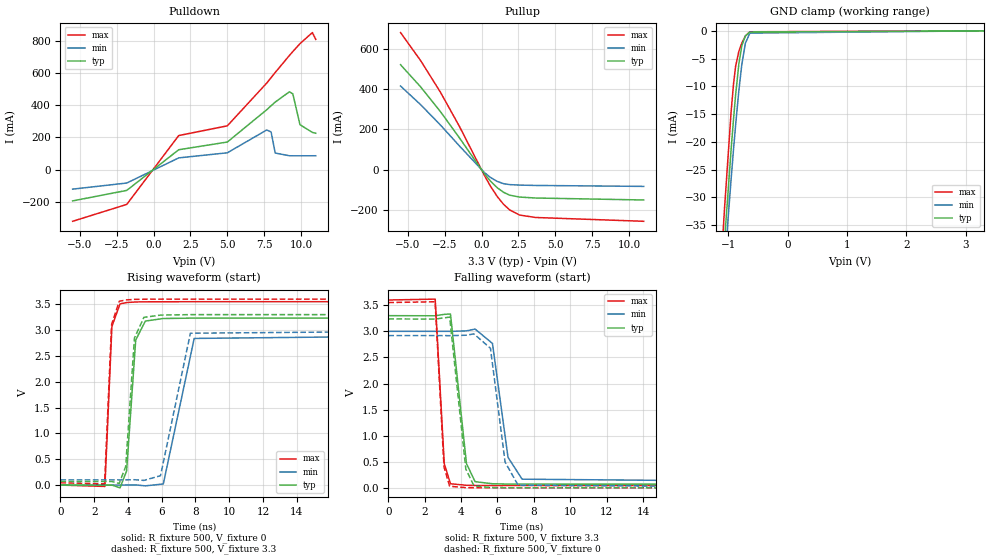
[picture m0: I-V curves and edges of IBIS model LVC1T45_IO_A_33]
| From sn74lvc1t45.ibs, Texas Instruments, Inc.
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[Model]   LVC1T45_IO_A_33
Model_type  I/O
Vinl=0.8
Vinh=2.0
Enable   Active-Low
Vref =   0
Rref =   2000
Cref =   15p
Vmeas =   1.65
| variable   typ   min   max
C_comp   6.86pF   5.92pF   8.09pF
| C_pullup   10.82pF   9.16pF   12.69pF
| C_pulldown   10.11pF   7.31pF   13.23pF
| C_tri-state   6.86pF   5.92pF   8.09pF
[Temperature Range]   40   100   -40
| Ambient temperature   25   85   -40
[Voltage range]   3.3   3   3.6
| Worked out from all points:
|   slope of the pulldown table from 0 to 0.495 V, typ, clamps not added: 11.2 ohm
|   slope of the pullup table from 0 to 0.495 V, typ, clamps not added: 10.6 ohm
|   GND clamp passes 1 mA (typ) near -0.71 V on its own axis
|   rising waveform, R_fixture 500, V_fixture 0: 20-80 % time 360ps typ, 624ps min, 211ps max; typ from 0 V to 3.23 V
|   falling waveform, R_fixture 500, V_fixture 3.3: 20-80 % time 352ps typ, 619ps min, 218ps max; typ from 3.3 V to 0.069 V
|   rising waveform, R_fixture 500, V_fixture 3.3: 20-80 % time 358ps typ, 630ps min, 216ps max; typ from 0.069 V to 3.3 V
|   falling waveform, R_fixture 500, V_fixture 0: 20-80 % time 344ps typ, 584ps min, 213ps max; typ from 3.24 V to 0 V
[GND Clamp]
| LVC1T45_IO_A_33
|   Voltage   I(typ)   I(min)   I(max)
-5.5V     -910.9mA   -836.3mA   -1.031A
-1.12V    -47.12mA   -50.9mA    -42.25mA
-1.09V    -42.34mA   -46.45mA   -36.95mA
-1.06V    -37.63mA   -42.05mA   -31.78mA
-950mV    -21.32mA   -26.62mA   -14.52mA
-910mV    -15.92mA   -21.37mA   -9.573mA
-875mV    -11.59mA   -17mA      -6.417mA
-820mV    -5.939mA   -10.75mA   -3.68mA
-770mV    -2.643mA   -6.035mA   -2.191mA
-710mV    -920.7uA   -2.212mA   -923.3uA
-635mV    -221.2uA   -410.8uA   -171uA
3.3V      10.41pA    35.81nA    8.12pA
[Pulldown]
| LVC1T45_IO_A_33
|   Voltage   I(typ)   I(min)   I(max)
-5.5V     -194.6mA   -121.5mA   -321.3mA
-1.825V   -129.3mA   -83.52mA   -216.3mA
1.7V      123.2mA    72.65mA    211.3mA
5V        171.2mA    104.3mA    271.8mA
7.675V    372mA      246.2mA    537.6mA
7.97V     396.6mA    233.5mA    571.4mA
8.25V     419.5mA    102.9mA    603.3mA
9.215V    483.4mA    85.88mA    709.4mA
9.445V    469.9mA    85.7mA     733.5mA
9.93V     278.8mA    85.68mA    782.4mA
10.77V    230.9mA    85.86mA    851.2mA
11V       225.9mA    85.92mA    808.7mA
[Pullup]
| LVC1T45_IO_A_33
|   Voltage   I(typ)   I(min)   I(max)
-5.5V     521mA      415.5mA    680.3mA
-4.125V   410.3mA    322.3mA    540.3mA
-2.79V    288.4mA    222mA      384.5mA
-1.5V     158.2mA    118.3mA    215mA
195mV     -19.51mA   -13.56mA   -27.85mA
640mV     -58.63mA   -39.42mA   -85.46mA
1.07V     -88.98mA   -57.5mA    -132.8mA
1.49V     -111.1mA   -68.41mA   -170.4mA
1.9V      -125.3mA   -73.08mA   -198.2mA
2.575V    -134.8mA   -75.52mA   -223.8mA
3.665V    -139.5mA   -77.22mA   -236mA
11V       -149.3mA   -81.96mA   -254.9mA
[Ramp]
| LVC1T45_IO_A_33
| variable   typ   min   max
dV/dt_r   1.98/3.73E-10   1.79/6.46E-10   2.16/2.23E-10
dV/dt_f   1.97/3.66E-10   1.77/6.35E-10   2.17/2.33E-10
R_load = 500
[Rising Waveform]
| LVC1T45_IO_A_33
R_fixture =   500
C_fixture =   0
L_fixture =   0
V_fixture =   0
V_fixture_min = 0
V_fixture_max = 0
|   Time   V(typ)   V(min)   V(max)
0s        168.9pV    331.3pV    105.2pV
2.635ns   535.9uV    -2.708uV   -26.37mV
3.05ns    328.1uV    25.37uV    3.071V
3.53ns    -54.05mV   -143.3uV   3.507V
3.92ns    272.3mV    949.2uV    3.534V
4.46ns    2.808V     3.006mV    3.545V
5.03ns    3.175V     -15.41mV   3.548V
6.095ns   3.225V     21.1mV     3.549V
7.925ns   3.233V     2.839V     3.55V
29.99ns   3.234V     2.914V     3.55V
[Falling Waveform]
| LVC1T45_IO_A_33
R_fixture =   500
C_fixture =   0
L_fixture =   0
V_fixture =   3.3
V_fixture_min = 3
V_fixture_max = 3.6
|   Time   V(typ)   V(min)   V(max)
0s        3.3V       3V         3.6V
2.575ns   3.298V     3V         3.617V
3.075ns   3.325V     3V         462.9mV
3.415ns   3.333V     2.999V     78.23mV
4.295ns   465.1mV    3.009V     49.31mV
4.77ns    118.4mV    3.043V     46.61mV
5.725ns   78.71mV    2.768V     44.83mV
6.58ns    72.54mV    585.1mV    44.39mV
7.355ns   70.73mV    166.2mV    44.25mV
29.99ns   69.38mV    100.9mV    44.1mV
[Rising Waveform]
| LVC1T45_IO_A_33
R_fixture =   500
C_fixture =   0
L_fixture =   0
V_fixture =   3.3
V_fixture_min = 3
V_fixture_max = 3.6
|   Time   V(typ)   V(min)   V(max)
0s        69.31mV    100.8mV    44.06mV
2.615ns   69.7mV     100.8mV    24.07mV
3.03ns    70.18mV    100.8mV    3.107V
3.48ns    30.68mV    100.6mV    3.557V
3.865ns   357.1mV    101.4mV    3.584V
4.385ns   2.846V     103.5mV    3.595V
4.945ns   3.247V     90.25mV    3.598V
5.93ns    3.291V     181.5mV    3.6V
7.7ns     3.3V       2.94V      3.6V
29.99ns   3.3V       3V         3.6V
[Falling Waveform]
| LVC1T45_IO_A_33
R_fixture =   500
C_fixture =   0
L_fixture =   0
V_fixture =   0
V_fixture_min = 0
V_fixture_max = 0
|   Time   V(typ)   V(min)   V(max)
0s        3.237V     2.918V     3.551V
2.57ns    3.235V     2.918V     3.567V
3.06ns    3.258V     2.918V     399.8mV
3.37ns    3.272V     2.917V     31mV
4.26ns    360.9mV    2.925V     4.439mV
4.705ns   39.48mV    2.951V     2.252mV
5.615ns   7.22mV     2.675V     712.3uV
6.42ns    2.499mV    493.6mV    318.2uV
7.135ns   1.128mV    52.09mV    185.7uV
29.99ns   70.43uV    137.7uV    35.57uV
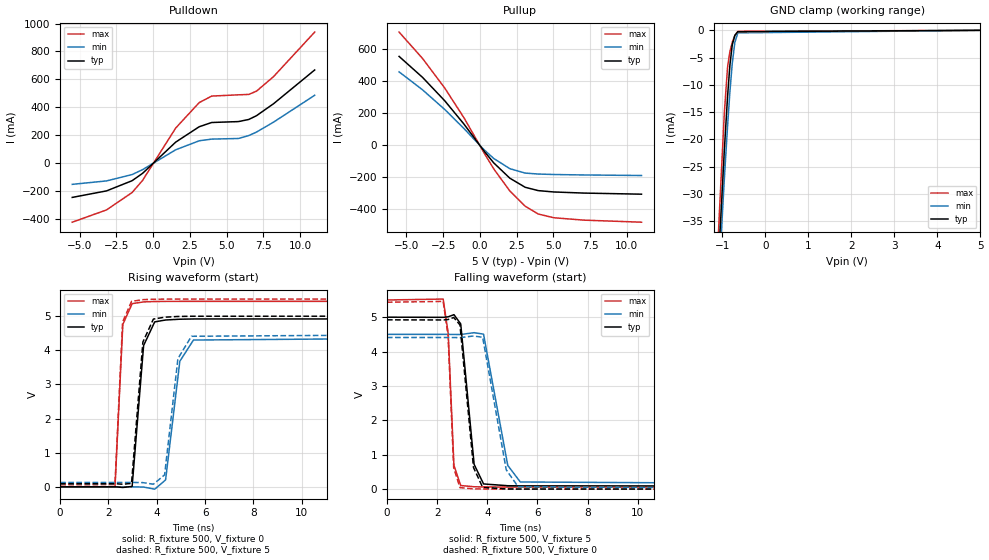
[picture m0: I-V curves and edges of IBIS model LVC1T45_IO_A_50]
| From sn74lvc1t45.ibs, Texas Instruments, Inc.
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[Model]   LVC1T45_IO_A_50
Model_type  I/O
Vinl=1.35
Vinh=3.85
Enable   Active-Low
Vref =   0
Rref =   2000
Cref =   15p
Vmeas =   2.5
| variable   typ   min   max
C_comp   6.40pF   5.43pF   7.87pF
| C_pullup   10.12pF   8.52pF   12.70pF
| C_pulldown   8.71pF   6.85pF   10.92pF
| C_tri-state   6.40pF   5.43pF   7.87pF
[Temperature Range]   40   100   -40
| Ambient temperature   25   85   -40
[Voltage range]   5   4.5   5.5
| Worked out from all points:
|   slope of the pulldown table from 0 to 0.75 V, typ, clamps not added: 9.75 ohm
|   slope of the pullup table from 0 to 0.75 V, typ, clamps not added: 8.46 ohm
|   GND clamp passes 1 mA (typ) near -0.71 V on its own axis
|   rising waveform, R_fixture 500, V_fixture 0: 20-80 % time 252ps typ, 390ps min, 153ps max; typ from 0 V to 4.92 V
|   falling waveform, R_fixture 500, V_fixture 5: 20-80 % time 277ps typ, 406ps min, 178ps max; typ from 5 V to 0.092 V
|   rising waveform, R_fixture 500, V_fixture 5: 20-80 % time 244ps typ, 377ps min, 152ps max; typ from 0.092 V to 5 V
|   falling waveform, R_fixture 500, V_fixture 0: 20-80 % time 275ps typ, 397ps min, 172ps max; typ from 4.92 V to 0 V
[GND Clamp]
| LVC1T45_IO_A_50
|   Voltage   I(typ)   I(min)   I(max)
-5.5V     -910.9mA   -836.3mA   -1.031A
-1.135V   -49.53mA   -53.14mA   -44.94mA
-1.12V    -47.12mA   -50.9mA    -42.25mA
-1.1V     -43.92mA   -47.92mA   -38.71mA
-1.07V    -39.19mA   -43.51mA   -33.49mA
-955mV    -22.02mA   -27.29mA   -15.21mA
-880mV    -12.18mA   -17.61mA   -6.789mA
-825mV    -6.376mA   -11.28mA   -3.86mA
-770mV    -2.643mA   -6.035mA   -2.191mA
-710mV    -920.7uA   -2.212mA   -923.3uA
-640mV    -245.9uA   -461.9uA   -195.8uA
5V        15.38pA    101.8nA    12.33pA
[Pulldown]
| LVC1T45_IO_A_50
|   Voltage   I(typ)   I(min)   I(max)
-5.5V     -247.8mA   -154.1mA   -425.7mA
-3.17V    -201.1mA   -129.5mA   -337.6mA
-1.43V    -128.1mA   -83.89mA   -213mA
-715mV    -75.2mA    -48.65mA   -125.8mA
1.54V     149mA      93.97mA    250mA
3.14V     259.4mA    158.6mA    432.6mA
3.99V     289.7mA    170.6mA    479.4mA
5.81V     296.3mA    175mA      488.4mA
6.515V    311.6mA    196.1mA    491.3mA
7.04V     338.7mA    221.1mA    514.8mA
8.205V    424.9mA    292.7mA    619.5mA
11V       666.8mA    485.2mA    938.6mA
[Pullup]
| LVC1T45_IO_A_50
|   Voltage   I(typ)   I(min)   I(max)
-5.5V     556.3mA    459.8mA    708.3mA
-3.9V     425mA      347.2mA    543mA
-2.385V   278.3mA    224.1mA    357.5mA
-1.08V    132.9mA    105.2mA    172.2mA
260mV     -32.41mA   -24.88mA   -42.78mA
945mV     -109.3mA   -81.77mA   -146.9mA
2.04V     -204.9mA   -145.3mA   -285mA
3.085V    -261.6mA   -172.9mA   -380mA
3.975V    -282.4mA   -178.8mA   -428.7mA
5.03V     -290.8mA   -181.7mA   -451.9mA
7.055V    -297.7mA   -184.5mA   -466.8mA
11V       -304.7mA   -188mA     -479.7mA
[Ramp]
| LVC1T45_IO_A_50
| variable   typ   min   max
dV/dt_r   2.99/2.63E-10   2.69/4.00E-10   3.30/1.61E-10
dV/dt_f   2.99/2.91E-10   2.66/4.21E-10   3.32/1.85E-10
R_load = 500
[Rising Waveform]
| LVC1T45_IO_A_50
R_fixture =   500
C_fixture =   0
L_fixture =   0
V_fixture =   0
V_fixture_min = 0
V_fixture_max = 0
|   Time   V(typ)   V(min)   V(max)
0s        225.7pV    389.5pV    145.6pV
2.27ns    2.056mV    38.75uV    -7.16mV
2.595ns   -17.16mV   -92.81uV   4.758V
2.98ns    12.86mV    1.984mV    5.366V
3.455ns   4.14V      -5.989mV   5.417V
3.915ns   4.832V     -67.18mV   5.428V
4.365ns   4.887V     203.4mV    5.431V
4.955ns   4.91V      3.679V     5.433V
5.52ns    4.917V     4.3V       5.433V
24.99ns   4.92V      4.406V     5.433V
[Falling Waveform]
| LVC1T45_IO_A_50
R_fixture =   500
C_fixture =   0
L_fixture =   0
V_fixture =   5
V_fixture_min = 4.5
V_fixture_max = 5.5
|   Time   V(typ)   V(min)   V(max)
0s        5V         4.5V       5.5V
2.24ns    4.996V     4.5V       5.527V
2.44ns    5.011V     4.5V       4.536V
2.67ns    5.073V     4.498V     691.2mV
2.94ns    4.805V     4.496V     105.1mV
3.475ns   720.4mV    4.55V      70.03mV
3.85ns    152.1mV    4.506V     64.85mV
4.815ns   99.98mV    691.1mV    61.17mV
5.315ns   95.69mV    208.9mV    60.67mV
24.99ns   91.93mV    128.8mV    60.15mV
[Rising Waveform]
| LVC1T45_IO_A_50
R_fixture =   500
C_fixture =   0
L_fixture =   0
V_fixture =   5
V_fixture_min = 4.5
V_fixture_max = 5.5
|   Time   V(typ)   V(min)   V(max)
0s        91.89mV    128.7mV    60.13mV
2.27ns    93.94mV    128.7mV    67.41mV
2.585ns   76.47mV    128.6mV    4.824V
2.955ns   101.7mV    130.4mV    5.432V
3.425ns   4.24V      124.6mV    5.483V
3.86ns    4.914V     77.89mV    5.494V
4.325ns   4.969V     351.4mV    5.498V
4.875ns   4.99V      3.756V     5.499V
5.435ns   4.997V     4.41V      5.5V
24.99ns   5V         4.5V       5.5V
[Falling Waveform]
| LVC1T45_IO_A_50
R_fixture =   500
C_fixture =   0
L_fixture =   0
V_fixture =   0
V_fixture_min = 0
V_fixture_max = 0
|   Time   V(typ)   V(min)   V(max)
0s        4.923V     4.41V      5.435V
2.24ns    4.919V     4.41V      5.459V
2.435ns   4.932V     4.41V      4.475V
2.66ns    4.991V     4.408V     624.1mV
2.91ns    4.776V     4.405V     44.54mV
3.45ns    629.4mV    4.453V     9.068mV
3.815ns   52.93mV    4.416V     4.396mV
4.755ns   6.967mV    563.1mV    994.9uV
5.23ns    3.351mV    67.88mV    527.3uV
24.99ns   37.65uV    72.57uV    18.81uV
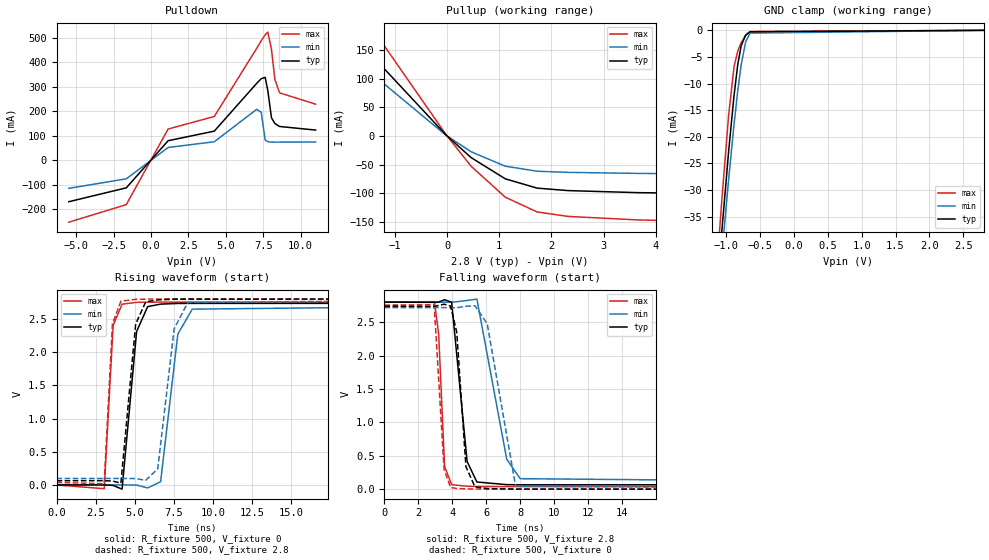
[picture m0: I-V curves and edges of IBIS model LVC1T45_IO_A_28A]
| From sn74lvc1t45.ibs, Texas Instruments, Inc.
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[Model]   LVC1T45_IO_A_28A
Model_type  I/O
Vinl=0.7
Vinh=1.7
Enable   Active-Low
Vref =   0
Rref =   2000
Cref =   15p
Vmeas =   1.25
| variable   typ   min   max
C_comp   7.02pF   6.20pF   8.13pF
| C_pullup   10.99pF   9.76pF   12.54pF
| C_pulldown   10.57pF   7.61pF   14.13pF
| C_tri-state   7.02pF   6.20pF   8.13pF
[Temperature Range]   40   100   -40
| Ambient temperature   25   85   -40
[Voltage range]   2.8   2.8   2.8
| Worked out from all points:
|   slope of the pulldown table from 0 to 0.42 V, typ, clamps not added: 12.3 ohm
|   slope of the pullup table from 0 to 0.42 V, typ, clamps not added: 12.2 ohm
|   GND clamp passes 1 mA (typ) near -0.71 V on its own axis
|   rising waveform, R_fixture 500, V_fixture 0: 20-80 % time 434ps typ, 689ps min, 276ps max; typ from 0 V to 2.74 V
|   falling waveform, R_fixture 500, V_fixture 2.8: 20-80 % time 417ps typ, 691ps min, 266ps max; typ from 2.8 V to 0.064 V
|   rising waveform, R_fixture 500, V_fixture 2.8: 20-80 % time 436ps typ, 703ps min, 278ps max; typ from 0.064 V to 2.8 V
|   falling waveform, R_fixture 500, V_fixture 0: 20-80 % time 402ps typ, 646ps min, 260ps max; typ from 2.74 V to 0 V
[GND Clamp]
| LVC1T45_IO_A_28A
|   Voltage   I(typ)   I(min)   I(max)
-5.5V     -910.9mA   -836.3mA   -1.031A
-1.14V    -50.34mA   -53.89mA   -45.85mA
-1.12V    -47.12mA   -50.9mA    -42.25mA
-1.075V   -39.97mA   -44.24mA   -34.35mA
-1.06V    -37.63mA   -42.05mA   -31.78mA
-960mV    -22.72mA   -27.97mA   -15.92mA
-880mV    -12.18mA   -17.61mA   -6.789mA
-825mV    -6.376mA   -11.28mA   -3.86mA
-775mV    -2.883mA   -6.453mA   -2.321mA
-710mV    -920.7uA   -2.212mA   -923.3uA
-645mV    -272.8uA   -519.5uA   -223.5uA
2.8V      8.953pA    15.32pA    7.945pA
[Pulldown]
| LVC1T45_IO_A_28A
|   Voltage   I(typ)   I(min)   I(max)
-5.5V     -169.9mA   -115.2mA   -253.7mA
-1.66V    -113.2mA   -76.45mA   -181.9mA
1.14V     79.49mA    51.82mA    127.3mA
4.225V    118.6mA    75.2mA     178.6mA
7.06V     313.9mA    207.7mA    457mA
7.365V    333.2mA    195.9mA    488.5mA
7.63V     338.4mA    81.63mA    512.9mA
7.805V    284.3mA    75.6mA     523.7mA
8.05V     173.3mA    73.9mA     453.3mA
8.28V     149.7mA    73.74mA    330mA
8.59V     137.7mA    73.76mA    275.3mA
11V       123mA      74.29mA    229mA
[Pullup]
| LVC1T45_IO_A_28A
|   Voltage   I(typ)   I(min)   I(max)
-5.5V     502.5mA    406.7mA    653.4mA
-2.51V    245.6mA    193.2mA    325.5mA
-2.015V   197.4mA    154.2mA    263mA
-1.895V   185.6mA    144.7mA    247.6mA
-1.435V   139.8mA    108.1mA    187.6mA
-20mV     1.83mA     1.366mA    2.531mA
460mV     -37.46mA   -27.37mA   -52.51mA
1.115V    -74.5mA    -52.48mA   -106.5mA
1.725V    -90.7mA    -61.27mA   -132.2mA
2.32V     -95.02mA   -63.26mA   -140mA
3.68V     -98.63mA   -65.12mA   -146.2mA
11V       -106.1mA   -69.35mA   -159mA
[Ramp]
| LVC1T45_IO_A_28A
| variable   typ   min   max
dV/dt_r   1.68/4.51E-10   1.68/7.19E-10   1.69/2.87E-10
dV/dt_f   1.67/4.32E-10   1.65/7.03E-10   1.69/2.77E-10
R_load = 500
[Rising Waveform]
| LVC1T45_IO_A_28A
R_fixture =   500
C_fixture =   0
L_fixture =   0
V_fixture =   0
V_fixture_min = 0
V_fixture_max = 0
|   Time   V(typ)   V(min)   V(max)
0s        154.7pV    326.9pV    90.5pV
3.05ns    1.159mV    18.75uV    -56.14mV
3.62ns    -6.991mV   -110uV     2.403V
4.19ns    -63.39mV   798.2uV    2.723V
5.12ns    2.311V     -2.132mV   2.75V
5.825ns   2.686V     -45.03mV   2.753V
6.655ns   2.724V     48.95mV    2.754V
7.755ns   2.734V     2.272V     2.754V
8.675ns   2.735V     2.648V     2.754V
34.99ns   2.736V     2.713V     2.754V
[Falling Waveform]
| LVC1T45_IO_A_28A
R_fixture =   500
C_fixture =   0
L_fixture =   0
V_fixture =   2.8
V_fixture_min = 2.8
V_fixture_max = 2.8
|   Time   V(typ)   V(min)   V(max)
0s        2.8V       2.8V       2.8V
2.94ns    2.797V     2.8V       2.807V
3.19ns    2.801V     2.8V       2.325V
3.54ns    2.836V     2.799V     338.9mV
3.955ns   2.798V     2.797V     67.93mV
4.865ns   413.9mV    2.825V     43.72mV
5.44ns    107.4mV    2.846V     40.79mV
7.195ns   67.75mV    450mV      38.76mV
7.985ns   65.61mV    157.2mV    38.59mV
34.99ns   63.86mV    97.93mV    38.4mV
[Rising Waveform]
| LVC1T45_IO_A_28A
R_fixture =   500
C_fixture =   0
L_fixture =   0
V_fixture =   2.8
V_fixture_min = 2.8
V_fixture_max = 2.8
|   Time   V(typ)   V(min)   V(max)
0s        63.77mV    97.78mV    38.36mV
3.045ns   64.86mV    97.8mV     18.41mV
3.575ns   59.04mV    97.68mV    2.425V
4.115ns   27.68mV    98.28mV    2.768V
5.06ns    2.423V     96.27mV    2.796V
5.7ns     2.757V     70.45mV    2.799V
6.47ns    2.788V     242.5mV    2.8V
7.52ns    2.798V     2.352V     2.8V
8.39ns    2.799V     2.748V     2.8V
34.99ns   2.8V       2.8V       2.8V
[Falling Waveform]
| LVC1T45_IO_A_28A
R_fixture =   500
C_fixture =   0
L_fixture =   0
V_fixture =   0
V_fixture_min = 0
V_fixture_max = 0
|   Time   V(typ)   V(min)   V(max)
0s        2.739V     2.718V     2.756V
2.925ns   2.736V     2.718V     2.761V
3.51ns    2.769V     2.718V     295.5mV
3.89ns    2.742V     2.716V     25.35mV
4.255ns   2.349V     2.717V     10.95mV
4.795ns   337.3mV    2.737V     4.365mV
5.325ns   35.08mV    2.747V     2.078mV
6.045ns   9.593mV    2.479V     886.1uV
7.72ns    1.333mV    45.35mV    223.1uV
34.99ns   76.96uV    133.8uV    39.59uV
